VERSION 5.7 ;
  NOWIREEXTENSIONATPIN ON ;
  DIVIDERCHAR "/" ;
  BUSBITCHARS "[]" ;
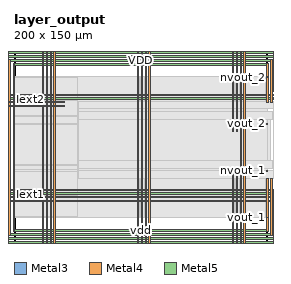
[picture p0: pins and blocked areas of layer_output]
MACRO layer_output
  CLASS BLOCK ;
  FOREIGN layer_output ;
  ORIGIN 0.000 0.000 ;
  SIZE 200.000 BY 150.000 ;
  PIN Iext1
    DIRECTION INPUT ;
    USE SIGNAL ;
    ANTENNAGATEAREA 0.280000 ;
    ANTENNADIFFAREA 1.380000 ;
    PORT
      LAYER Metal3 ;
        RECT 0.000 36.960 0.560 37.520 ;
    END
  END Iext1
  PIN Iext2
    DIRECTION INPUT ;
    USE SIGNAL ;
    ANTENNAGATEAREA 0.280000 ;
    ANTENNADIFFAREA 1.380000 ;
    PORT
      LAYER Metal3 ;
        RECT 0.000 112.000 0.560 112.560 ;
    END
  END Iext2
  PIN VDD
    DIRECTION INOUT ;
    USE POWER ;
    PORT
      LAYER Metal4 ;
        RECT -7.180 1.780 -5.680 147.180 ;
    END
    PORT
      LAYER Metal4 ;
        RECT 205.600 1.780 207.100 40.690 ;
    END
    PORT
      LAYER Metal4 ;
        RECT 205.600 119.620 207.100 147.180 ;
    END
    PORT
      LAYER Metal5 ;
        RECT -7.180 1.780 207.100 3.280 ;
    END
    PORT
      LAYER Metal5 ;
        RECT -7.180 145.680 207.100 147.180 ;
    END
    PORT
      LAYER Metal4 ;
        RECT 28.540 -1.420 29.540 150.380 ;
    END
    PORT
      LAYER Metal4 ;
        RECT 103.540 -1.420 104.540 150.380 ;
    END
    PORT
      LAYER Metal4 ;
        RECT 178.540 -1.420 179.540 150.380 ;
    END
    PORT
      LAYER Metal5 ;
        RECT -10.380 37.830 210.300 38.830 ;
    END
    PORT
      LAYER Metal5 ;
        RECT -10.380 112.830 210.300 113.830 ;
    END
  END VDD
  PIN VSS
    DIRECTION INOUT ;
    USE GROUND ;
    PORT
      LAYER Metal4 ;
        RECT -10.380 -1.420 -8.880 150.380 ;
    END
    PORT
      LAYER Metal4 ;
        RECT 208.800 -1.420 210.300 41.200 ;
    END
    PORT
      LAYER Metal4 ;
        RECT 208.800 119.120 210.300 150.380 ;
    END
    PORT
      LAYER Metal5 ;
        RECT -10.380 -1.420 210.300 0.080 ;
    END
    PORT
      LAYER Metal5 ;
        RECT -10.380 148.880 210.300 150.380 ;
    END
    PORT
      LAYER Metal4 ;
        RECT 31.540 -1.420 32.540 150.380 ;
    END
    PORT
      LAYER Metal4 ;
        RECT 106.540 -1.420 107.540 150.380 ;
    END
    PORT
      LAYER Metal4 ;
        RECT 181.540 -1.420 182.540 150.380 ;
    END
    PORT
      LAYER Metal5 ;
        RECT -10.380 40.830 210.300 41.830 ;
    END
    PORT
      LAYER Metal5 ;
        RECT -10.380 115.830 210.300 116.830 ;
    END
  END VSS
  PIN nvout_1
    DIRECTION OUTPUT ;
    USE SIGNAL ;
    ANTENNAGATEAREA 0.560000 ;
    ANTENNADIFFAREA 0.750000 ;
    PORT
      LAYER Metal3 ;
        RECT 199.440 56.000 200.000 56.560 ;
    END
  END nvout_1
  PIN nvout_2
    DIRECTION OUTPUT ;
    USE SIGNAL ;
    ANTENNAGATEAREA 0.560000 ;
    ANTENNADIFFAREA 0.750000 ;
    PORT
      LAYER Metal3 ;
        RECT 199.440 129.920 200.000 130.480 ;
    END
  END nvout_2
  PIN vdd
    DIRECTION INOUT ;
    USE POWER ;
    PORT
      LAYER Metal4 ;
        RECT -0.780 8.180 0.720 140.780 ;
    END
    PORT
      LAYER Metal4 ;
        RECT 199.200 8.180 200.700 49.820 ;
    END
    PORT
      LAYER Metal4 ;
        RECT 199.200 110.490 200.700 140.780 ;
    END
    PORT
      LAYER Metal5 ;
        RECT -0.780 8.180 200.700 9.680 ;
    END
    PORT
      LAYER Metal5 ;
        RECT -0.780 139.280 200.700 140.780 ;
    END
    PORT
      LAYER Metal4 ;
        RECT 22.540 -1.420 23.540 150.380 ;
    END
    PORT
      LAYER Metal4 ;
        RECT 97.540 -1.420 98.540 150.380 ;
    END
    PORT
      LAYER Metal4 ;
        RECT 172.540 -1.420 173.540 58.700 ;
    END
    PORT
      LAYER Metal4 ;
        RECT 172.540 86.920 173.540 150.380 ;
    END
    PORT
      LAYER Metal5 ;
        RECT -10.380 31.830 210.300 32.830 ;
    END
    PORT
      LAYER Metal5 ;
        RECT -10.380 106.830 40.080 107.830 ;
    END
  END vdd
  PIN vout_1
    DIRECTION OUTPUT ;
    USE SIGNAL ;
    ANTENNADIFFAREA 0.750000 ;
    PORT
      LAYER Metal3 ;
        RECT 199.440 19.040 200.000 19.600 ;
    END
  END vout_1
  PIN vout_2
    DIRECTION OUTPUT ;
    USE SIGNAL ;
    ANTENNADIFFAREA 0.750000 ;
    PORT
      LAYER Metal3 ;
        RECT 199.440 92.960 200.000 93.520 ;
    END
  END vout_2
  PIN vss
    DIRECTION INOUT ;
    USE GROUND ;
    PORT
      LAYER Metal4 ;
        RECT -3.980 4.980 -2.480 143.980 ;
    END
    PORT
      LAYER Metal4 ;
        RECT 202.400 4.980 203.900 50.320 ;
    END
    PORT
      LAYER Metal4 ;
        RECT 202.400 109.990 203.900 143.980 ;
    END
    PORT
      LAYER Metal5 ;
        RECT -3.980 4.980 203.900 6.480 ;
    END
    PORT
      LAYER Metal5 ;
        RECT -3.980 142.480 203.900 143.980 ;
    END
    PORT
      LAYER Metal4 ;
        RECT 25.540 -1.420 26.540 150.380 ;
    END
    PORT
      LAYER Metal4 ;
        RECT 100.540 -1.420 101.540 150.380 ;
    END
    PORT
      LAYER Metal4 ;
        RECT 175.540 -1.420 176.540 58.700 ;
    END
    PORT
      LAYER Metal4 ;
        RECT 175.540 86.920 176.540 150.380 ;
    END
    PORT
      LAYER Metal5 ;
        RECT -10.380 34.830 210.300 35.830 ;
    END
    PORT
      LAYER Metal5 ;
        RECT -10.380 109.830 40.080 110.830 ;
    END
  END vss
  OBS
      LAYER Nwell ;
        RECT 63.000 70.430 196.860 91.020 ;
      LAYER Metal1 ;
        RECT 63.190 70.640 196.630 90.810 ;
      LAYER Metal2 ;
        RECT 52.250 99.900 200.000 109.030 ;
        RECT 206.750 108.530 207.250 109.030 ;
        RECT 52.250 99.400 200.250 99.900 ;
        RECT 52.250 60.850 200.000 99.400 ;
        RECT 52.250 60.350 200.250 60.850 ;
        RECT 52.250 51.720 200.000 60.350 ;
        RECT 52.250 51.220 207.250 51.720 ;
      LAYER Metal3 ;
        RECT 0.560 129.620 199.140 130.340 ;
        RECT 0.560 112.860 200.000 129.620 ;
        RECT 0.860 111.700 200.000 112.860 ;
        RECT 0.560 99.900 200.000 111.700 ;
        RECT 206.750 108.530 207.250 109.030 ;
        RECT 0.560 99.400 200.250 99.900 ;
        RECT 0.560 93.820 200.000 99.400 ;
        RECT 0.560 92.660 199.140 93.820 ;
        RECT 0.560 60.850 200.000 92.660 ;
        RECT 0.560 60.350 200.250 60.850 ;
        RECT 0.560 56.860 200.000 60.350 ;
        RECT 0.560 55.700 199.140 56.860 ;
        RECT 0.560 37.820 200.000 55.700 ;
        RECT 206.750 51.220 207.250 51.720 ;
        RECT 0.860 36.660 200.000 37.820 ;
        RECT 0.560 19.900 200.000 36.660 ;
        RECT 0.560 19.180 199.140 19.900 ;
      LAYER Metal4 ;
        RECT 50.000 19.130 97.240 130.390 ;
        RECT 98.840 19.130 100.240 130.390 ;
        RECT 101.840 19.130 103.240 130.390 ;
        RECT 104.840 19.130 106.240 130.390 ;
        RECT 107.840 86.620 172.240 130.390 ;
        RECT 173.840 86.620 175.240 130.390 ;
        RECT 176.840 86.620 178.240 130.390 ;
        RECT 107.840 59.000 178.240 86.620 ;
        RECT 107.840 19.130 172.240 59.000 ;
        RECT 173.840 19.130 175.240 59.000 ;
        RECT 176.840 19.130 178.240 59.000 ;
        RECT 179.840 19.130 181.240 130.390 ;
        RECT 182.840 110.190 198.900 130.390 ;
        RECT 182.840 99.900 200.000 110.190 ;
        RECT 206.750 108.530 207.250 109.030 ;
        RECT 182.840 99.430 200.250 99.900 ;
        RECT 182.840 60.850 202.500 99.430 ;
        RECT 182.840 60.350 200.250 60.850 ;
        RECT 182.840 50.120 200.000 60.350 ;
        RECT 204.500 51.720 209.500 108.530 ;
        RECT 206.750 51.220 207.250 51.720 ;
        RECT 202.400 50.320 203.900 50.350 ;
        RECT 182.840 19.130 198.900 50.120 ;
      LAYER Metal5 ;
        RECT 51.000 111.280 200.000 111.310 ;
        RECT 202.400 111.280 203.900 111.310 ;
        RECT 51.000 105.150 208.860 111.280 ;
        RECT 51.000 103.150 200.000 105.150 ;
        RECT 51.000 97.020 203.860 103.150 ;
        RECT 51.000 64.260 200.000 97.020 ;
        RECT 51.000 64.230 202.500 64.260 ;
        RECT 51.000 58.100 203.860 64.230 ;
        RECT 51.000 56.100 200.000 58.100 ;
        RECT 51.000 49.970 208.860 56.100 ;
  END
END layer_output
END LIBRARY

